##
## LEF for PtnCells ;
## created by Innovus v15.23-s045_1 on Sat Mar 21 00:23:04 2026
##

VERSION 5.8 ;

BUSBITCHARS "[]" ;
DIVIDERCHAR "/" ;

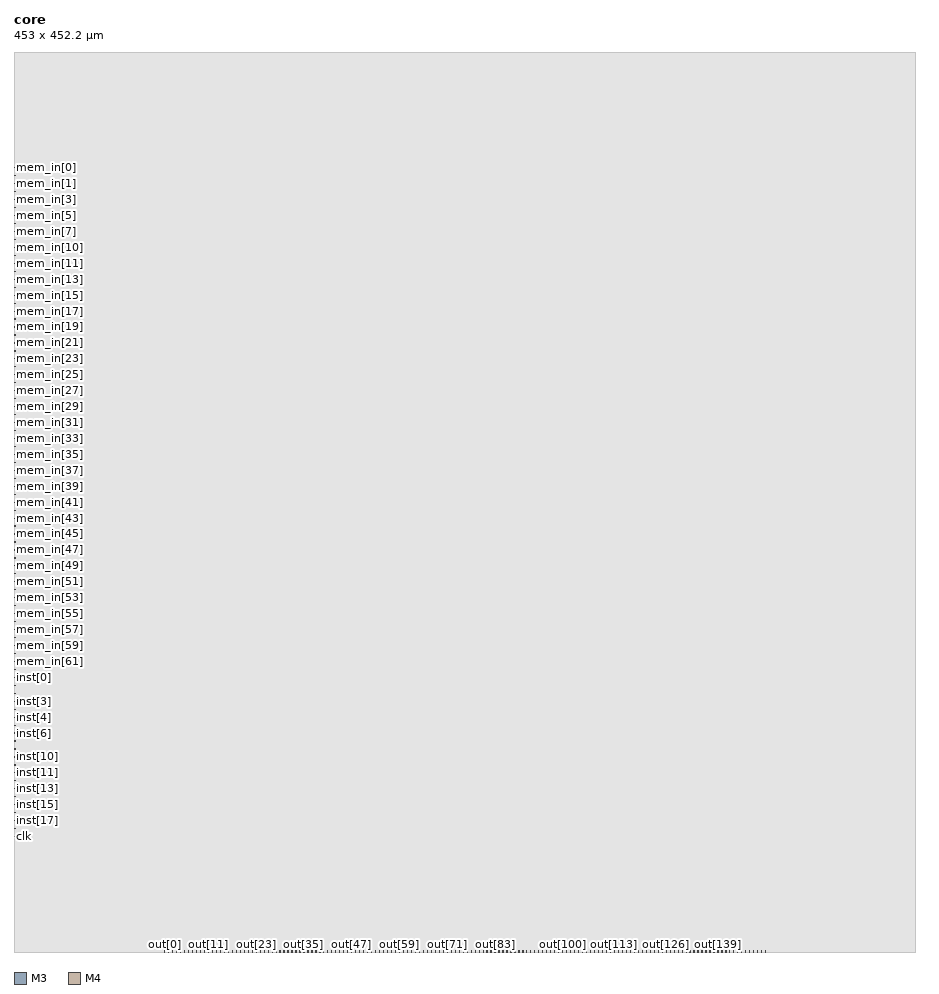
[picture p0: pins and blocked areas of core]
MACRO core
  CLASS BLOCK ;
  SIZE 453.0000 BY 452.2000 ;
  FOREIGN core 0.0000 0.0000 ;
  ORIGIN 0 0 ;
  SYMMETRY X Y R90 ;
  PIN clk
    DIRECTION INPUT ;
    USE SIGNAL ;
    PORT
      LAYER M3 ;
        RECT 0.0000 57.9500 0.5200 58.0500 ;
    END
  END clk
  PIN mem_in[63]
    DIRECTION INPUT ;
    USE SIGNAL ;
    PORT
      LAYER M3 ;
        RECT 0.0000 141.9500 0.5200 142.0500 ;
    END
  END mem_in[63]
  PIN mem_in[62]
    DIRECTION INPUT ;
    USE SIGNAL ;
    PORT
      LAYER M3 ;
        RECT 0.0000 145.9500 0.5200 146.0500 ;
    END
  END mem_in[62]
  PIN mem_in[61]
    DIRECTION INPUT ;
    USE SIGNAL ;
    PORT
      LAYER M3 ;
        RECT 0.0000 149.9500 0.5200 150.0500 ;
    END
  END mem_in[61]
  PIN mem_in[60]
    DIRECTION INPUT ;
    USE SIGNAL ;
    PORT
      LAYER M3 ;
        RECT 0.0000 153.9500 0.5200 154.0500 ;
    END
  END mem_in[60]
  PIN mem_in[59]
    DIRECTION INPUT ;
    USE SIGNAL ;
    PORT
      LAYER M3 ;
        RECT 0.0000 157.9500 0.5200 158.0500 ;
    END
  END mem_in[59]
  PIN mem_in[58]
    DIRECTION INPUT ;
    USE SIGNAL ;
    PORT
      LAYER M3 ;
        RECT 0.0000 161.9500 0.5200 162.0500 ;
    END
  END mem_in[58]
  PIN mem_in[57]
    DIRECTION INPUT ;
    USE SIGNAL ;
    PORT
      LAYER M3 ;
        RECT 0.0000 165.9500 0.5200 166.0500 ;
    END
  END mem_in[57]
  PIN mem_in[56]
    DIRECTION INPUT ;
    USE SIGNAL ;
    PORT
      LAYER M3 ;
        RECT 0.0000 169.9500 0.5200 170.0500 ;
    END
  END mem_in[56]
  PIN mem_in[55]
    DIRECTION INPUT ;
    USE SIGNAL ;
    PORT
      LAYER M3 ;
        RECT 0.0000 173.9500 0.5200 174.0500 ;
    END
  END mem_in[55]
  PIN mem_in[54]
    DIRECTION INPUT ;
    USE SIGNAL ;
    PORT
      LAYER M3 ;
        RECT 0.0000 177.9500 0.5200 178.0500 ;
    END
  END mem_in[54]
  PIN mem_in[53]
    DIRECTION INPUT ;
    USE SIGNAL ;
    PORT
      LAYER M3 ;
        RECT 0.0000 181.9500 0.5200 182.0500 ;
    END
  END mem_in[53]
  PIN mem_in[52]
    DIRECTION INPUT ;
    USE SIGNAL ;
    PORT
      LAYER M3 ;
        RECT 0.0000 185.9500 0.5200 186.0500 ;
    END
  END mem_in[52]
  PIN mem_in[51]
    DIRECTION INPUT ;
    USE SIGNAL ;
    PORT
      LAYER M3 ;
        RECT 0.0000 189.9500 0.5200 190.0500 ;
    END
  END mem_in[51]
  PIN mem_in[50]
    DIRECTION INPUT ;
    USE SIGNAL ;
    PORT
      LAYER M3 ;
        RECT 0.0000 193.9500 0.5200 194.0500 ;
    END
  END mem_in[50]
  PIN mem_in[49]
    DIRECTION INPUT ;
    USE SIGNAL ;
    PORT
      LAYER M3 ;
        RECT 0.0000 197.9500 0.5200 198.0500 ;
    END
  END mem_in[49]
  PIN mem_in[48]
    DIRECTION INPUT ;
    USE SIGNAL ;
    PORT
      LAYER M3 ;
        RECT 0.0000 201.9500 0.5200 202.0500 ;
    END
  END mem_in[48]
  PIN mem_in[47]
    DIRECTION INPUT ;
    USE SIGNAL ;
    PORT
      LAYER M3 ;
        RECT 0.0000 205.9500 0.5200 206.0500 ;
    END
  END mem_in[47]
  PIN mem_in[46]
    DIRECTION INPUT ;
    USE SIGNAL ;
    PORT
      LAYER M3 ;
        RECT 0.0000 209.9500 0.5200 210.0500 ;
    END
  END mem_in[46]
  PIN mem_in[45]
    DIRECTION INPUT ;
    USE SIGNAL ;
    PORT
      LAYER M3 ;
        RECT 0.0000 213.9500 0.5200 214.0500 ;
    END
  END mem_in[45]
  PIN mem_in[44]
    DIRECTION INPUT ;
    USE SIGNAL ;
    PORT
      LAYER M3 ;
        RECT 0.0000 217.9500 0.5200 218.0500 ;
    END
  END mem_in[44]
  PIN mem_in[43]
    DIRECTION INPUT ;
    USE SIGNAL ;
    PORT
      LAYER M3 ;
        RECT 0.0000 221.9500 0.5200 222.0500 ;
    END
  END mem_in[43]
  PIN mem_in[42]
    DIRECTION INPUT ;
    USE SIGNAL ;
    PORT
      LAYER M3 ;
        RECT 0.0000 225.9500 0.5200 226.0500 ;
    END
  END mem_in[42]
  PIN mem_in[41]
    DIRECTION INPUT ;
    USE SIGNAL ;
    PORT
      LAYER M3 ;
        RECT 0.0000 229.9500 0.5200 230.0500 ;
    END
  END mem_in[41]
  PIN mem_in[40]
    DIRECTION INPUT ;
    USE SIGNAL ;
    PORT
      LAYER M3 ;
        RECT 0.0000 233.9500 0.5200 234.0500 ;
    END
  END mem_in[40]
  PIN mem_in[39]
    DIRECTION INPUT ;
    USE SIGNAL ;
    PORT
      LAYER M3 ;
        RECT 0.0000 237.9500 0.5200 238.0500 ;
    END
  END mem_in[39]
  PIN mem_in[38]
    DIRECTION INPUT ;
    USE SIGNAL ;
    PORT
      LAYER M3 ;
        RECT 0.0000 241.9500 0.5200 242.0500 ;
    END
  END mem_in[38]
  PIN mem_in[37]
    DIRECTION INPUT ;
    USE SIGNAL ;
    PORT
      LAYER M3 ;
        RECT 0.0000 245.9500 0.5200 246.0500 ;
    END
  END mem_in[37]
  PIN mem_in[36]
    DIRECTION INPUT ;
    USE SIGNAL ;
    PORT
      LAYER M3 ;
        RECT 0.0000 249.9500 0.5200 250.0500 ;
    END
  END mem_in[36]
  PIN mem_in[35]
    DIRECTION INPUT ;
    USE SIGNAL ;
    PORT
      LAYER M3 ;
        RECT 0.0000 253.9500 0.5200 254.0500 ;
    END
  END mem_in[35]
  PIN mem_in[34]
    DIRECTION INPUT ;
    USE SIGNAL ;
    PORT
      LAYER M3 ;
        RECT 0.0000 257.9500 0.5200 258.0500 ;
    END
  END mem_in[34]
  PIN mem_in[33]
    DIRECTION INPUT ;
    USE SIGNAL ;
    PORT
      LAYER M3 ;
        RECT 0.0000 261.9500 0.5200 262.0500 ;
    END
  END mem_in[33]
  PIN mem_in[32]
    DIRECTION INPUT ;
    USE SIGNAL ;
    PORT
      LAYER M3 ;
        RECT 0.0000 265.9500 0.5200 266.0500 ;
    END
  END mem_in[32]
  PIN mem_in[31]
    DIRECTION INPUT ;
    USE SIGNAL ;
    PORT
      LAYER M3 ;
        RECT 0.0000 269.9500 0.5200 270.0500 ;
    END
  END mem_in[31]
  PIN mem_in[30]
    DIRECTION INPUT ;
    USE SIGNAL ;
    PORT
      LAYER M3 ;
        RECT 0.0000 273.9500 0.5200 274.0500 ;
    END
  END mem_in[30]
  PIN mem_in[29]
    DIRECTION INPUT ;
    USE SIGNAL ;
    PORT
      LAYER M3 ;
        RECT 0.0000 277.9500 0.5200 278.0500 ;
    END
  END mem_in[29]
  PIN mem_in[28]
    DIRECTION INPUT ;
    USE SIGNAL ;
    PORT
      LAYER M3 ;
        RECT 0.0000 281.9500 0.5200 282.0500 ;
    END
  END mem_in[28]
  PIN mem_in[27]
    DIRECTION INPUT ;
    USE SIGNAL ;
    PORT
      LAYER M3 ;
        RECT 0.0000 285.9500 0.5200 286.0500 ;
    END
  END mem_in[27]
  PIN mem_in[26]
    DIRECTION INPUT ;
    USE SIGNAL ;
    PORT
      LAYER M3 ;
        RECT 0.0000 289.9500 0.5200 290.0500 ;
    END
  END mem_in[26]
  PIN mem_in[25]
    DIRECTION INPUT ;
    USE SIGNAL ;
    PORT
      LAYER M3 ;
        RECT 0.0000 293.9500 0.5200 294.0500 ;
    END
  END mem_in[25]
  PIN mem_in[24]
    DIRECTION INPUT ;
    USE SIGNAL ;
    PORT
      LAYER M3 ;
        RECT 0.0000 297.9500 0.5200 298.0500 ;
    END
  END mem_in[24]
  PIN mem_in[23]
    DIRECTION INPUT ;
    USE SIGNAL ;
    PORT
      LAYER M3 ;
        RECT 0.0000 301.9500 0.5200 302.0500 ;
    END
  END mem_in[23]
  PIN mem_in[22]
    DIRECTION INPUT ;
    USE SIGNAL ;
    PORT
      LAYER M3 ;
        RECT 0.0000 305.9500 0.5200 306.0500 ;
    END
  END mem_in[22]
  PIN mem_in[21]
    DIRECTION INPUT ;
    USE SIGNAL ;
    PORT
      LAYER M3 ;
        RECT 0.0000 309.9500 0.5200 310.0500 ;
    END
  END mem_in[21]
  PIN mem_in[20]
    DIRECTION INPUT ;
    USE SIGNAL ;
    PORT
      LAYER M3 ;
        RECT 0.0000 313.9500 0.5200 314.0500 ;
    END
  END mem_in[20]
  PIN mem_in[19]
    DIRECTION INPUT ;
    USE SIGNAL ;
    PORT
      LAYER M3 ;
        RECT 0.0000 317.9500 0.5200 318.0500 ;
    END
  END mem_in[19]
  PIN mem_in[18]
    DIRECTION INPUT ;
    USE SIGNAL ;
    PORT
      LAYER M3 ;
        RECT 0.0000 321.9500 0.5200 322.0500 ;
    END
  END mem_in[18]
  PIN mem_in[17]
    DIRECTION INPUT ;
    USE SIGNAL ;
    PORT
      LAYER M3 ;
        RECT 0.0000 325.9500 0.5200 326.0500 ;
    END
  END mem_in[17]
  PIN mem_in[16]
    DIRECTION INPUT ;
    USE SIGNAL ;
    PORT
      LAYER M3 ;
        RECT 0.0000 329.9500 0.5200 330.0500 ;
    END
  END mem_in[16]
  PIN mem_in[15]
    DIRECTION INPUT ;
    USE SIGNAL ;
    PORT
      LAYER M3 ;
        RECT 0.0000 333.9500 0.5200 334.0500 ;
    END
  END mem_in[15]
  PIN mem_in[14]
    DIRECTION INPUT ;
    USE SIGNAL ;
    PORT
      LAYER M3 ;
        RECT 0.0000 337.9500 0.5200 338.0500 ;
    END
  END mem_in[14]
  PIN mem_in[13]
    DIRECTION INPUT ;
    USE SIGNAL ;
    PORT
      LAYER M3 ;
        RECT 0.0000 341.9500 0.5200 342.0500 ;
    END
  END mem_in[13]
  PIN mem_in[12]
    DIRECTION INPUT ;
    USE SIGNAL ;
    PORT
      LAYER M3 ;
        RECT 0.0000 345.9500 0.5200 346.0500 ;
    END
  END mem_in[12]
  PIN mem_in[11]
    DIRECTION INPUT ;
    USE SIGNAL ;
    PORT
      LAYER M3 ;
        RECT 0.0000 349.9500 0.5200 350.0500 ;
    END
  END mem_in[11]
  PIN mem_in[10]
    DIRECTION INPUT ;
    USE SIGNAL ;
    PORT
      LAYER M3 ;
        RECT 0.0000 353.9500 0.5200 354.0500 ;
    END
  END mem_in[10]
  PIN mem_in[9]
    DIRECTION INPUT ;
    USE SIGNAL ;
    PORT
      LAYER M3 ;
        RECT 0.0000 357.9500 0.5200 358.0500 ;
    END
  END mem_in[9]
  PIN mem_in[8]
    DIRECTION INPUT ;
    USE SIGNAL ;
    PORT
      LAYER M3 ;
        RECT 0.0000 361.9500 0.5200 362.0500 ;
    END
  END mem_in[8]
  PIN mem_in[7]
    DIRECTION INPUT ;
    USE SIGNAL ;
    PORT
      LAYER M3 ;
        RECT 0.0000 365.9500 0.5200 366.0500 ;
    END
  END mem_in[7]
  PIN mem_in[6]
    DIRECTION INPUT ;
    USE SIGNAL ;
    PORT
      LAYER M3 ;
        RECT 0.0000 369.9500 0.5200 370.0500 ;
    END
  END mem_in[6]
  PIN mem_in[5]
    DIRECTION INPUT ;
    USE SIGNAL ;
    PORT
      LAYER M3 ;
        RECT 0.0000 373.9500 0.5200 374.0500 ;
    END
  END mem_in[5]
  PIN mem_in[4]
    DIRECTION INPUT ;
    USE SIGNAL ;
    PORT
      LAYER M3 ;
        RECT 0.0000 377.9500 0.5200 378.0500 ;
    END
  END mem_in[4]
  PIN mem_in[3]
    DIRECTION INPUT ;
    USE SIGNAL ;
    PORT
      LAYER M3 ;
        RECT 0.0000 381.9500 0.5200 382.0500 ;
    END
  END mem_in[3]
  PIN mem_in[2]
    DIRECTION INPUT ;
    USE SIGNAL ;
    PORT
      LAYER M3 ;
        RECT 0.0000 385.9500 0.5200 386.0500 ;
    END
  END mem_in[2]
  PIN mem_in[1]
    DIRECTION INPUT ;
    USE SIGNAL ;
    PORT
      LAYER M3 ;
        RECT 0.0000 389.9500 0.5200 390.0500 ;
    END
  END mem_in[1]
  PIN mem_in[0]
    DIRECTION INPUT ;
    USE SIGNAL ;
    PORT
      LAYER M3 ;
        RECT 0.0000 393.9500 0.5200 394.0500 ;
    END
  END mem_in[0]
  PIN inst[18]
    DIRECTION INPUT ;
    USE SIGNAL ;
    PORT
      LAYER M3 ;
        RECT 0.0000 65.9500 0.5200 66.0500 ;
    END
  END inst[18]
  PIN inst[17]
    DIRECTION INPUT ;
    USE SIGNAL ;
    PORT
      LAYER M3 ;
        RECT 0.0000 69.9500 0.5200 70.0500 ;
    END
  END inst[17]
  PIN inst[16]
    DIRECTION INPUT ;
    USE SIGNAL ;
    PORT
      LAYER M3 ;
        RECT 0.0000 73.9500 0.5200 74.0500 ;
    END
  END inst[16]
  PIN inst[15]
    DIRECTION INPUT ;
    USE SIGNAL ;
    PORT
      LAYER M3 ;
        RECT 0.0000 77.9500 0.5200 78.0500 ;
    END
  END inst[15]
  PIN inst[14]
    DIRECTION INPUT ;
    USE SIGNAL ;
    PORT
      LAYER M3 ;
        RECT 0.0000 81.9500 0.5200 82.0500 ;
    END
  END inst[14]
  PIN inst[13]
    DIRECTION INPUT ;
    USE SIGNAL ;
    PORT
      LAYER M3 ;
        RECT 0.0000 85.9500 0.5200 86.0500 ;
    END
  END inst[13]
  PIN inst[12]
    DIRECTION INPUT ;
    USE SIGNAL ;
    PORT
      LAYER M3 ;
        RECT 0.0000 89.9500 0.5200 90.0500 ;
    END
  END inst[12]
  PIN inst[11]
    DIRECTION INPUT ;
    USE SIGNAL ;
    PORT
      LAYER M3 ;
        RECT 0.0000 93.9500 0.5200 94.0500 ;
    END
  END inst[11]
  PIN inst[10]
    DIRECTION INPUT ;
    USE SIGNAL ;
    PORT
      LAYER M3 ;
        RECT 0.0000 97.9500 0.5200 98.0500 ;
    END
  END inst[10]
  PIN inst[9]
    DIRECTION INPUT ;
    USE SIGNAL ;
    PORT
      LAYER M3 ;
        RECT 0.0000 101.9500 0.5200 102.0500 ;
    END
  END inst[9]
  PIN inst[8]
    DIRECTION INPUT ;
    USE SIGNAL ;
    PORT
      LAYER M3 ;
        RECT 0.0000 105.9500 0.5200 106.0500 ;
    END
  END inst[8]
  PIN inst[7]
    DIRECTION INPUT ;
    USE SIGNAL ;
    PORT
      LAYER M3 ;
        RECT 0.0000 109.9500 0.5200 110.0500 ;
    END
  END inst[7]
  PIN inst[6]
    DIRECTION INPUT ;
    USE SIGNAL ;
    PORT
      LAYER M3 ;
        RECT 0.0000 113.9500 0.5200 114.0500 ;
    END
  END inst[6]
  PIN inst[5]
    DIRECTION INPUT ;
    USE SIGNAL ;
    PORT
      LAYER M3 ;
        RECT 0.0000 117.9500 0.5200 118.0500 ;
    END
  END inst[5]
  PIN inst[4]
    DIRECTION INPUT ;
    USE SIGNAL ;
    PORT
      LAYER M3 ;
        RECT 0.0000 121.9500 0.5200 122.0500 ;
    END
  END inst[4]
  PIN inst[3]
    DIRECTION INPUT ;
    USE SIGNAL ;
    PORT
      LAYER M3 ;
        RECT 0.0000 125.9500 0.5200 126.0500 ;
    END
  END inst[3]
  PIN inst[2]
    DIRECTION INPUT ;
    USE SIGNAL ;
    PORT
      LAYER M3 ;
        RECT 0.0000 129.9500 0.5200 130.0500 ;
    END
  END inst[2]
  PIN inst[1]
    DIRECTION INPUT ;
    USE SIGNAL ;
    PORT
      LAYER M3 ;
        RECT 0.0000 133.9500 0.5200 134.0500 ;
    END
  END inst[1]
  PIN inst[0]
    DIRECTION INPUT ;
    USE SIGNAL ;
    PORT
      LAYER M3 ;
        RECT 0.0000 137.9500 0.5200 138.0500 ;
    END
  END inst[0]
  PIN reset
    DIRECTION INPUT ;
    USE SIGNAL ;
    PORT
      LAYER M3 ;
        RECT 0.0000 61.9500 0.5200 62.0500 ;
    END
  END reset
  PIN out[151]
    DIRECTION OUTPUT ;
    USE SIGNAL ;
    PORT
      LAYER M4 ;
        RECT 377.6500 0.0000 377.7500 0.5200 ;
    END
  END out[151]
  PIN out[150]
    DIRECTION OUTPUT ;
    USE SIGNAL ;
    PORT
      LAYER M4 ;
        RECT 375.6500 0.0000 375.7500 0.5200 ;
    END
  END out[150]
  PIN out[149]
    DIRECTION OUTPUT ;
    USE SIGNAL ;
    PORT
      LAYER M4 ;
        RECT 373.6500 0.0000 373.7500 0.5200 ;
    END
  END out[149]
  PIN out[148]
    DIRECTION OUTPUT ;
    USE SIGNAL ;
    PORT
      LAYER M4 ;
        RECT 371.6500 0.0000 371.7500 0.5200 ;
    END
  END out[148]
  PIN out[147]
    DIRECTION OUTPUT ;
    USE SIGNAL ;
    PORT
      LAYER M4 ;
        RECT 369.6500 0.0000 369.7500 0.5200 ;
    END
  END out[147]
  PIN out[146]
    DIRECTION OUTPUT ;
    USE SIGNAL ;
    PORT
      LAYER M4 ;
        RECT 367.6500 0.0000 367.7500 0.5200 ;
    END
  END out[146]
  PIN out[145]
    DIRECTION OUTPUT ;
    USE SIGNAL ;
    PORT
      LAYER M4 ;
        RECT 365.6500 0.0000 365.7500 0.5200 ;
    END
  END out[145]
  PIN out[144]
    DIRECTION OUTPUT ;
    USE SIGNAL ;
    PORT
      LAYER M4 ;
        RECT 363.6500 0.0000 363.7500 0.5200 ;
    END
  END out[144]
  PIN out[143]
    DIRECTION OUTPUT ;
    USE SIGNAL ;
    PORT
      LAYER M4 ;
        RECT 361.6500 0.0000 361.7500 0.5200 ;
    END
  END out[143]
  PIN out[142]
    DIRECTION OUTPUT ;
    USE SIGNAL ;
    PORT
      LAYER M4 ;
        RECT 359.6500 0.0000 359.7500 0.5200 ;
    END
  END out[142]
  PIN out[141]
    DIRECTION OUTPUT ;
    USE SIGNAL ;
    PORT
      LAYER M4 ;
        RECT 357.6500 0.0000 357.7500 0.5200 ;
    END
  END out[141]
  PIN out[140]
    DIRECTION OUTPUT ;
    USE SIGNAL ;
    PORT
      LAYER M4 ;
        RECT 355.6500 0.0000 355.7500 0.5200 ;
    END
  END out[140]
  PIN out[139]
    DIRECTION OUTPUT ;
    USE SIGNAL ;
    PORT
      LAYER M4 ;
        RECT 353.6500 0.0000 353.7500 0.5200 ;
    END
  END out[139]
  PIN out[138]
    DIRECTION OUTPUT ;
    USE SIGNAL ;
    PORT
      LAYER M4 ;
        RECT 351.6500 0.0000 351.7500 0.5200 ;
    END
  END out[138]
  PIN out[137]
    DIRECTION OUTPUT ;
    USE SIGNAL ;
    PORT
      LAYER M4 ;
        RECT 349.6500 0.0000 349.7500 0.5200 ;
    END
  END out[137]
  PIN out[136]
    DIRECTION OUTPUT ;
    USE SIGNAL ;
    PORT
      LAYER M4 ;
        RECT 347.6500 0.0000 347.7500 0.5200 ;
    END
  END out[136]
  PIN out[135]
    DIRECTION OUTPUT ;
    USE SIGNAL ;
    PORT
      LAYER M4 ;
        RECT 345.6500 0.0000 345.7500 0.5200 ;
    END
  END out[135]
  PIN out[134]
    DIRECTION OUTPUT ;
    USE SIGNAL ;
    PORT
      LAYER M4 ;
        RECT 343.6500 0.0000 343.7500 0.5200 ;
    END
  END out[134]
  PIN out[133]
    DIRECTION OUTPUT ;
    USE SIGNAL ;
    PORT
      LAYER M4 ;
        RECT 341.6500 0.0000 341.7500 0.5200 ;
    END
  END out[133]
  PIN out[132]
    DIRECTION OUTPUT ;
    USE SIGNAL ;
    PORT
      LAYER M4 ;
        RECT 339.6500 0.0000 339.7500 0.5200 ;
    END
  END out[132]
  PIN out[131]
    DIRECTION OUTPUT ;
    USE SIGNAL ;
    PORT
      LAYER M4 ;
        RECT 337.6500 0.0000 337.7500 0.5200 ;
    END
  END out[131]
  PIN out[130]
    DIRECTION OUTPUT ;
    USE SIGNAL ;
    PORT
      LAYER M4 ;
        RECT 335.6500 0.0000 335.7500 0.5200 ;
    END
  END out[130]
  PIN out[129]
    DIRECTION OUTPUT ;
    USE SIGNAL ;
    PORT
      LAYER M4 ;
        RECT 333.6500 0.0000 333.7500 0.5200 ;
    END
  END out[129]
  PIN out[128]
    DIRECTION OUTPUT ;
    USE SIGNAL ;
    PORT
      LAYER M4 ;
        RECT 331.6500 0.0000 331.7500 0.5200 ;
    END
  END out[128]
  PIN out[127]
    DIRECTION OUTPUT ;
    USE SIGNAL ;
    PORT
      LAYER M4 ;
        RECT 329.6500 0.0000 329.7500 0.5200 ;
    END
  END out[127]
  PIN out[126]
    DIRECTION OUTPUT ;
    USE SIGNAL ;
    PORT
      LAYER M4 ;
        RECT 327.6500 0.0000 327.7500 0.5200 ;
    END
  END out[126]
  PIN out[125]
    DIRECTION OUTPUT ;
    USE SIGNAL ;
    PORT
      LAYER M4 ;
        RECT 325.6500 0.0000 325.7500 0.5200 ;
    END
  END out[125]
  PIN out[124]
    DIRECTION OUTPUT ;
    USE SIGNAL ;
    PORT
      LAYER M4 ;
        RECT 323.6500 0.0000 323.7500 0.5200 ;
    END
  END out[124]
  PIN out[123]
    DIRECTION OUTPUT ;
    USE SIGNAL ;
    PORT
      LAYER M4 ;
        RECT 321.6500 0.0000 321.7500 0.5200 ;
    END
  END out[123]
  PIN out[122]
    DIRECTION OUTPUT ;
    USE SIGNAL ;
    PORT
      LAYER M4 ;
        RECT 319.6500 0.0000 319.7500 0.5200 ;
    END
  END out[122]
  PIN out[121]
    DIRECTION OUTPUT ;
    USE SIGNAL ;
    PORT
      LAYER M4 ;
        RECT 317.6500 0.0000 317.7500 0.5200 ;
    END
  END out[121]
  PIN out[120]
    DIRECTION OUTPUT ;
    USE SIGNAL ;
    PORT
      LAYER M4 ;
        RECT 315.6500 0.0000 315.7500 0.5200 ;
    END
  END out[120]
  PIN out[119]
    DIRECTION OUTPUT ;
    USE SIGNAL ;
    PORT
      LAYER M4 ;
        RECT 313.6500 0.0000 313.7500 0.5200 ;
    END
  END out[119]
  PIN out[118]
    DIRECTION OUTPUT ;
    USE SIGNAL ;
    PORT
      LAYER M4 ;
        RECT 311.6500 0.0000 311.7500 0.5200 ;
    END
  END out[118]
  PIN out[117]
    DIRECTION OUTPUT ;
    USE SIGNAL ;
    PORT
      LAYER M4 ;
        RECT 309.6500 0.0000 309.7500 0.5200 ;
    END
  END out[117]
  PIN out[116]
    DIRECTION OUTPUT ;
    USE SIGNAL ;
    PORT
      LAYER M4 ;
        RECT 307.6500 0.0000 307.7500 0.5200 ;
    END
  END out[116]
  PIN out[115]
    DIRECTION OUTPUT ;
    USE SIGNAL ;
    PORT
      LAYER M4 ;
        RECT 305.6500 0.0000 305.7500 0.5200 ;
    END
  END out[115]
  PIN out[114]
    DIRECTION OUTPUT ;
    USE SIGNAL ;
    PORT
      LAYER M4 ;
        RECT 303.6500 0.0000 303.7500 0.5200 ;
    END
  END out[114]
  PIN out[113]
    DIRECTION OUTPUT ;
    USE SIGNAL ;
    PORT
      LAYER M4 ;
        RECT 301.6500 0.0000 301.7500 0.5200 ;
    END
  END out[113]
  PIN out[112]
    DIRECTION OUTPUT ;
    USE SIGNAL ;
    PORT
      LAYER M4 ;
        RECT 299.6500 0.0000 299.7500 0.5200 ;
    END
  END out[112]
  PIN out[111]
    DIRECTION OUTPUT ;
    USE SIGNAL ;
    PORT
      LAYER M4 ;
        RECT 297.6500 0.0000 297.7500 0.5200 ;
    END
  END out[111]
  PIN out[110]
    DIRECTION OUTPUT ;
    USE SIGNAL ;
    PORT
      LAYER M4 ;
        RECT 295.6500 0.0000 295.7500 0.5200 ;
    END
  END out[110]
  PIN out[109]
    DIRECTION OUTPUT ;
    USE SIGNAL ;
    PORT
      LAYER M4 ;
        RECT 293.6500 0.0000 293.7500 0.5200 ;
    END
  END out[109]
  PIN out[108]
    DIRECTION OUTPUT ;
    USE SIGNAL ;
    PORT
      LAYER M4 ;
        RECT 291.6500 0.0000 291.7500 0.5200 ;
    END
  END out[108]
  PIN out[107]
    DIRECTION OUTPUT ;
    USE SIGNAL ;
    PORT
      LAYER M4 ;
        RECT 289.6500 0.0000 289.7500 0.5200 ;
    END
  END out[107]
  PIN out[106]
    DIRECTION OUTPUT ;
    USE SIGNAL ;
    PORT
      LAYER M4 ;
        RECT 287.6500 0.0000 287.7500 0.5200 ;
    END
  END out[106]
  PIN out[105]
    DIRECTION OUTPUT ;
    USE SIGNAL ;
    PORT
      LAYER M4 ;
        RECT 285.6500 0.0000 285.7500 0.5200 ;
    END
  END out[105]
  PIN out[104]
    DIRECTION OUTPUT ;
    USE SIGNAL ;
    PORT
      LAYER M4 ;
        RECT 283.6500 0.0000 283.7500 0.5200 ;
    END
  END out[104]
  PIN out[103]
    DIRECTION OUTPUT ;
    USE SIGNAL ;
    PORT
      LAYER M4 ;
        RECT 281.6500 0.0000 281.7500 0.5200 ;
    END
  END out[103]
  PIN out[102]
    DIRECTION OUTPUT ;
    USE SIGNAL ;
    PORT
      LAYER M4 ;
        RECT 279.6500 0.0000 279.7500 0.5200 ;
    END
  END out[102]
  PIN out[101]
    DIRECTION OUTPUT ;
    USE SIGNAL ;
    PORT
      LAYER M4 ;
        RECT 277.6500 0.0000 277.7500 0.5200 ;
    END
  END out[101]
  PIN out[100]
    DIRECTION OUTPUT ;
    USE SIGNAL ;
    PORT
      LAYER M4 ;
        RECT 275.6500 0.0000 275.7500 0.5200 ;
    END
  END out[100]
  PIN out[99]
    DIRECTION OUTPUT ;
    USE SIGNAL ;
    PORT
      LAYER M4 ;
        RECT 273.6500 0.0000 273.7500 0.5200 ;
    END
  END out[99]
  PIN out[98]
    DIRECTION OUTPUT ;
    USE SIGNAL ;
    PORT
      LAYER M4 ;
        RECT 271.6500 0.0000 271.7500 0.5200 ;
    END
  END out[98]
  PIN out[97]
    DIRECTION OUTPUT ;
    USE SIGNAL ;
    PORT
      LAYER M4 ;
        RECT 269.6500 0.0000 269.7500 0.5200 ;
    END
  END out[97]
  PIN out[96]
    DIRECTION OUTPUT ;
    USE SIGNAL ;
    PORT
      LAYER M4 ;
        RECT 267.6500 0.0000 267.7500 0.5200 ;
    END
  END out[96]
  PIN out[95]
    DIRECTION OUTPUT ;
    USE SIGNAL ;
    PORT
      LAYER M4 ;
        RECT 265.6500 0.0000 265.7500 0.5200 ;
    END
  END out[95]
  PIN out[94]
    DIRECTION OUTPUT ;
    USE SIGNAL ;
    PORT
      LAYER M4 ;
        RECT 263.6500 0.0000 263.7500 0.5200 ;
    END
  END out[94]
  PIN out[93]
    DIRECTION OUTPUT ;
    USE SIGNAL ;
    PORT
      LAYER M4 ;
        RECT 261.6500 0.0000 261.7500 0.5200 ;
    END
  END out[93]
  PIN out[92]
    DIRECTION OUTPUT ;
    USE SIGNAL ;
    PORT
      LAYER M4 ;
        RECT 259.6500 0.0000 259.7500 0.5200 ;
    END
  END out[92]
  PIN out[91]
    DIRECTION OUTPUT ;
    USE SIGNAL ;
    PORT
      LAYER M4 ;
        RECT 257.6500 0.0000 257.7500 0.5200 ;
    END
  END out[91]
  PIN out[90]
    DIRECTION OUTPUT ;
    USE SIGNAL ;
    PORT
      LAYER M4 ;
        RECT 255.6500 0.0000 255.7500 0.5200 ;
    END
  END out[90]
  PIN out[89]
    DIRECTION OUTPUT ;
    USE SIGNAL ;
    PORT
      LAYER M4 ;
        RECT 253.6500 0.0000 253.7500 0.5200 ;
    END
  END out[89]
  PIN out[88]
    DIRECTION OUTPUT ;
    USE SIGNAL ;
    PORT
      LAYER M4 ;
        RECT 251.6500 0.0000 251.7500 0.5200 ;
    END
  END out[88]
  PIN out[87]
    DIRECTION OUTPUT ;
    USE SIGNAL ;
    PORT
      LAYER M4 ;
        RECT 249.6500 0.0000 249.7500 0.5200 ;
    END
  END out[87]
  PIN out[86]
    DIRECTION OUTPUT ;
    USE SIGNAL ;
    PORT
      LAYER M4 ;
        RECT 247.6500 0.0000 247.7500 0.5200 ;
    END
  END out[86]
  PIN out[85]
    DIRECTION OUTPUT ;
    USE SIGNAL ;
    PORT
      LAYER M4 ;
        RECT 245.6500 0.0000 245.7500 0.5200 ;
    END
  END out[85]
  PIN out[84]
    DIRECTION OUTPUT ;
    USE SIGNAL ;
    PORT
      LAYER M4 ;
        RECT 243.6500 0.0000 243.7500 0.5200 ;
    END
  END out[84]
  PIN out[83]
    DIRECTION OUTPUT ;
    USE SIGNAL ;
    PORT
      LAYER M4 ;
        RECT 241.6500 0.0000 241.7500 0.5200 ;
    END
  END out[83]
  PIN out[82]
    DIRECTION OUTPUT ;
    USE SIGNAL ;
    PORT
      LAYER M4 ;
        RECT 239.6500 0.0000 239.7500 0.5200 ;
    END
  END out[82]
  PIN out[81]
    DIRECTION OUTPUT ;
    USE SIGNAL ;
    PORT
      LAYER M4 ;
        RECT 237.6500 0.0000 237.7500 0.5200 ;
    END
  END out[81]
  PIN out[80]
    DIRECTION OUTPUT ;
    USE SIGNAL ;
    PORT
      LAYER M4 ;
        RECT 235.6500 0.0000 235.7500 0.5200 ;
    END
  END out[80]
  PIN out[79]
    DIRECTION OUTPUT ;
    USE SIGNAL ;
    PORT
      LAYER M4 ;
        RECT 233.6500 0.0000 233.7500 0.5200 ;
    END
  END out[79]
  PIN out[78]
    DIRECTION OUTPUT ;
    USE SIGNAL ;
    PORT
      LAYER M4 ;
        RECT 231.6500 0.0000 231.7500 0.5200 ;
    END
  END out[78]
  PIN out[77]
    DIRECTION OUTPUT ;
    USE SIGNAL ;
    PORT
      LAYER M4 ;
        RECT 229.6500 0.0000 229.7500 0.5200 ;
    END
  END out[77]
  PIN out[76]
    DIRECTION OUTPUT ;
    USE SIGNAL ;
    PORT
      LAYER M4 ;
        RECT 227.6500 0.0000 227.7500 0.5200 ;
    END
  END out[76]
  PIN out[75]
    DIRECTION OUTPUT ;
    USE SIGNAL ;
    PORT
      LAYER M4 ;
        RECT 225.6500 0.0000 225.7500 0.5200 ;
    END
  END out[75]
  PIN out[74]
    DIRECTION OUTPUT ;
    USE SIGNAL ;
    PORT
      LAYER M4 ;
        RECT 223.6500 0.0000 223.7500 0.5200 ;
    END
  END out[74]
  PIN out[73]
    DIRECTION OUTPUT ;
    USE SIGNAL ;
    PORT
      LAYER M4 ;
        RECT 221.6500 0.0000 221.7500 0.5200 ;
    END
  END out[73]
  PIN out[72]
    DIRECTION OUTPUT ;
    USE SIGNAL ;
    PORT
      LAYER M4 ;
        RECT 219.6500 0.0000 219.7500 0.5200 ;
    END
  END out[72]
  PIN out[71]
    DIRECTION OUTPUT ;
    USE SIGNAL ;
    PORT
      LAYER M4 ;
        RECT 217.6500 0.0000 217.7500 0.5200 ;
    END
  END out[71]
  PIN out[70]
    DIRECTION OUTPUT ;
    USE SIGNAL ;
    PORT
      LAYER M4 ;
        RECT 215.6500 0.0000 215.7500 0.5200 ;
    END
  END out[70]
  PIN out[69]
    DIRECTION OUTPUT ;
    USE SIGNAL ;
    PORT
      LAYER M4 ;
        RECT 213.6500 0.0000 213.7500 0.5200 ;
    END
  END out[69]
  PIN out[68]
    DIRECTION OUTPUT ;
    USE SIGNAL ;
    PORT
      LAYER M4 ;
        RECT 211.6500 0.0000 211.7500 0.5200 ;
    END
  END out[68]
  PIN out[67]
    DIRECTION OUTPUT ;
    USE SIGNAL ;
    PORT
      LAYER M4 ;
        RECT 209.6500 0.0000 209.7500 0.5200 ;
    END
  END out[67]
  PIN out[66]
    DIRECTION OUTPUT ;
    USE SIGNAL ;
    PORT
      LAYER M4 ;
        RECT 207.6500 0.0000 207.7500 0.5200 ;
    END
  END out[66]
  PIN out[65]
    DIRECTION OUTPUT ;
    USE SIGNAL ;
    PORT
      LAYER M4 ;
        RECT 205.6500 0.0000 205.7500 0.5200 ;
    END
  END out[65]
  PIN out[64]
    DIRECTION OUTPUT ;
    USE SIGNAL ;
    PORT
      LAYER M4 ;
        RECT 203.6500 0.0000 203.7500 0.5200 ;
    END
  END out[64]
  PIN out[63]
    DIRECTION OUTPUT ;
    USE SIGNAL ;
    PORT
      LAYER M4 ;
        RECT 201.6500 0.0000 201.7500 0.5200 ;
    END
  END out[63]
  PIN out[62]
    DIRECTION OUTPUT ;
    USE SIGNAL ;
    PORT
      LAYER M4 ;
        RECT 199.6500 0.0000 199.7500 0.5200 ;
    END
  END out[62]
  PIN out[61]
    DIRECTION OUTPUT ;
    USE SIGNAL ;
    PORT
      LAYER M4 ;
        RECT 197.6500 0.0000 197.7500 0.5200 ;
    END
  END out[61]
  PIN out[60]
    DIRECTION OUTPUT ;
    USE SIGNAL ;
    PORT
      LAYER M4 ;
        RECT 195.6500 0.0000 195.7500 0.5200 ;
    END
  END out[60]
  PIN out[59]
    DIRECTION OUTPUT ;
    USE SIGNAL ;
    PORT
      LAYER M4 ;
        RECT 193.6500 0.0000 193.7500 0.5200 ;
    END
  END out[59]
  PIN out[58]
    DIRECTION OUTPUT ;
    USE SIGNAL ;
    PORT
      LAYER M4 ;
        RECT 191.6500 0.0000 191.7500 0.5200 ;
    END
  END out[58]
  PIN out[57]
    DIRECTION OUTPUT ;
    USE SIGNAL ;
    PORT
      LAYER M4 ;
        RECT 189.6500 0.0000 189.7500 0.5200 ;
    END
  END out[57]
  PIN out[56]
    DIRECTION OUTPUT ;
    USE SIGNAL ;
    PORT
      LAYER M4 ;
        RECT 187.6500 0.0000 187.7500 0.5200 ;
    END
  END out[56]
  PIN out[55]
    DIRECTION OUTPUT ;
    USE SIGNAL ;
    PORT
      LAYER M4 ;
        RECT 185.6500 0.0000 185.7500 0.5200 ;
    END
  END out[55]
  PIN out[54]
    DIRECTION OUTPUT ;
    USE SIGNAL ;
    PORT
      LAYER M4 ;
        RECT 183.6500 0.0000 183.7500 0.5200 ;
    END
  END out[54]
  PIN out[53]
    DIRECTION OUTPUT ;
    USE SIGNAL ;
    PORT
      LAYER M4 ;
        RECT 181.6500 0.0000 181.7500 0.5200 ;
    END
  END out[53]
  PIN out[52]
    DIRECTION OUTPUT ;
    USE SIGNAL ;
    PORT
      LAYER M4 ;
        RECT 179.6500 0.0000 179.7500 0.5200 ;
    END
  END out[52]
  PIN out[51]
    DIRECTION OUTPUT ;
    USE SIGNAL ;
    PORT
      LAYER M4 ;
        RECT 177.6500 0.0000 177.7500 0.5200 ;
    END
  END out[51]
  PIN out[50]
    DIRECTION OUTPUT ;
    USE SIGNAL ;
    PORT
      LAYER M4 ;
        RECT 175.6500 0.0000 175.7500 0.5200 ;
    END
  END out[50]
  PIN out[49]
    DIRECTION OUTPUT ;
    USE SIGNAL ;
    PORT
      LAYER M4 ;
        RECT 173.6500 0.0000 173.7500 0.5200 ;
    END
  END out[49]
  PIN out[48]
    DIRECTION OUTPUT ;
    USE SIGNAL ;
    PORT
      LAYER M4 ;
        RECT 171.6500 0.0000 171.7500 0.5200 ;
    END
  END out[48]
  PIN out[47]
    DIRECTION OUTPUT ;
    USE SIGNAL ;
    PORT
      LAYER M4 ;
        RECT 169.6500 0.0000 169.7500 0.5200 ;
    END
  END out[47]
  PIN out[46]
    DIRECTION OUTPUT ;
    USE SIGNAL ;
    PORT
      LAYER M4 ;
        RECT 167.6500 0.0000 167.7500 0.5200 ;
    END
  END out[46]
  PIN out[45]
    DIRECTION OUTPUT ;
    USE SIGNAL ;
    PORT
      LAYER M4 ;
        RECT 165.6500 0.0000 165.7500 0.5200 ;
    END
  END out[45]
  PIN out[44]
    DIRECTION OUTPUT ;
    USE SIGNAL ;
    PORT
      LAYER M4 ;
        RECT 163.6500 0.0000 163.7500 0.5200 ;
    END
  END out[44]
  PIN out[43]
    DIRECTION OUTPUT ;
    USE SIGNAL ;
    PORT
      LAYER M4 ;
        RECT 161.6500 0.0000 161.7500 0.5200 ;
    END
  END out[43]
  PIN out[42]
    DIRECTION OUTPUT ;
    USE SIGNAL ;
    PORT
      LAYER M4 ;
        RECT 159.6500 0.0000 159.7500 0.5200 ;
    END
  END out[42]
  PIN out[41]
    DIRECTION OUTPUT ;
    USE SIGNAL ;
    PORT
      LAYER M4 ;
        RECT 157.6500 0.0000 157.7500 0.5200 ;
    END
  END out[41]
  PIN out[40]
    DIRECTION OUTPUT ;
    USE SIGNAL ;
    PORT
      LAYER M4 ;
        RECT 155.6500 0.0000 155.7500 0.5200 ;
    END
  END out[40]
  PIN out[39]
    DIRECTION OUTPUT ;
    USE SIGNAL ;
    PORT
      LAYER M4 ;
        RECT 153.6500 0.0000 153.7500 0.5200 ;
    END
  END out[39]
  PIN out[38]
    DIRECTION OUTPUT ;
    USE SIGNAL ;
    PORT
      LAYER M4 ;
        RECT 151.6500 0.0000 151.7500 0.5200 ;
    END
  END out[38]
  PIN out[37]
    DIRECTION OUTPUT ;
    USE SIGNAL ;
    PORT
      LAYER M4 ;
        RECT 149.6500 0.0000 149.7500 0.5200 ;
    END
  END out[37]
  PIN out[36]
    DIRECTION OUTPUT ;
    USE SIGNAL ;
    PORT
      LAYER M4 ;
        RECT 147.6500 0.0000 147.7500 0.5200 ;
    END
  END out[36]
  PIN out[35]
    DIRECTION OUTPUT ;
    USE SIGNAL ;
    PORT
      LAYER M4 ;
        RECT 145.6500 0.0000 145.7500 0.5200 ;
    END
  END out[35]
  PIN out[34]
    DIRECTION OUTPUT ;
    USE SIGNAL ;
    PORT
      LAYER M4 ;
        RECT 143.6500 0.0000 143.7500 0.5200 ;
    END
  END out[34]
  PIN out[33]
    DIRECTION OUTPUT ;
    USE SIGNAL ;
    PORT
      LAYER M4 ;
        RECT 141.6500 0.0000 141.7500 0.5200 ;
    END
  END out[33]
  PIN out[32]
    DIRECTION OUTPUT ;
    USE SIGNAL ;
    PORT
      LAYER M4 ;
        RECT 139.6500 0.0000 139.7500 0.5200 ;
    END
  END out[32]
  PIN out[31]
    DIRECTION OUTPUT ;
    USE SIGNAL ;
    PORT
      LAYER M4 ;
        RECT 137.6500 0.0000 137.7500 0.5200 ;
    END
  END out[31]
  PIN out[30]
    DIRECTION OUTPUT ;
    USE SIGNAL ;
    PORT
      LAYER M4 ;
        RECT 135.6500 0.0000 135.7500 0.5200 ;
    END
  END out[30]
  PIN out[29]
    DIRECTION OUTPUT ;
    USE SIGNAL ;
    PORT
      LAYER M4 ;
        RECT 133.6500 0.0000 133.7500 0.5200 ;
    END
  END out[29]
  PIN out[28]
    DIRECTION OUTPUT ;
    USE SIGNAL ;
    PORT
      LAYER M4 ;
        RECT 131.6500 0.0000 131.7500 0.5200 ;
    END
  END out[28]
  PIN out[27]
    DIRECTION OUTPUT ;
    USE SIGNAL ;
    PORT
      LAYER M4 ;
        RECT 129.6500 0.0000 129.7500 0.5200 ;
    END
  END out[27]
  PIN out[26]
    DIRECTION OUTPUT ;
    USE SIGNAL ;
    PORT
      LAYER M4 ;
        RECT 127.6500 0.0000 127.7500 0.5200 ;
    END
  END out[26]
  PIN out[25]
    DIRECTION OUTPUT ;
    USE SIGNAL ;
    PORT
      LAYER M4 ;
        RECT 125.6500 0.0000 125.7500 0.5200 ;
    END
  END out[25]
  PIN out[24]
    DIRECTION OUTPUT ;
    USE SIGNAL ;
    PORT
      LAYER M4 ;
        RECT 123.6500 0.0000 123.7500 0.5200 ;
    END
  END out[24]
  PIN out[23]
    DIRECTION OUTPUT ;
    USE SIGNAL ;
    PORT
      LAYER M4 ;
        RECT 121.6500 0.0000 121.7500 0.5200 ;
    END
  END out[23]
  PIN out[22]
    DIRECTION OUTPUT ;
    USE SIGNAL ;
    PORT
      LAYER M4 ;
        RECT 119.6500 0.0000 119.7500 0.5200 ;
    END
  END out[22]
  PIN out[21]
    DIRECTION OUTPUT ;
    USE SIGNAL ;
    PORT
      LAYER M4 ;
        RECT 117.6500 0.0000 117.7500 0.5200 ;
    END
  END out[21]
  PIN out[20]
    DIRECTION OUTPUT ;
    USE SIGNAL ;
    PORT
      LAYER M4 ;
        RECT 115.6500 0.0000 115.7500 0.5200 ;
    END
  END out[20]
  PIN out[19]
    DIRECTION OUTPUT ;
    USE SIGNAL ;
    PORT
      LAYER M4 ;
        RECT 113.6500 0.0000 113.7500 0.5200 ;
    END
  END out[19]
  PIN out[18]
    DIRECTION OUTPUT ;
    USE SIGNAL ;
    PORT
      LAYER M4 ;
        RECT 111.6500 0.0000 111.7500 0.5200 ;
    END
  END out[18]
  PIN out[17]
    DIRECTION OUTPUT ;
    USE SIGNAL ;
    PORT
      LAYER M4 ;
        RECT 109.6500 0.0000 109.7500 0.5200 ;
    END
  END out[17]
  PIN out[16]
    DIRECTION OUTPUT ;
    USE SIGNAL ;
    PORT
      LAYER M4 ;
        RECT 107.6500 0.0000 107.7500 0.5200 ;
    END
  END out[16]
  PIN out[15]
    DIRECTION OUTPUT ;
    USE SIGNAL ;
    PORT
      LAYER M4 ;
        RECT 105.6500 0.0000 105.7500 0.5200 ;
    END
  END out[15]
  PIN out[14]
    DIRECTION OUTPUT ;
    USE SIGNAL ;
    PORT
      LAYER M4 ;
        RECT 103.6500 0.0000 103.7500 0.5200 ;
    END
  END out[14]
  PIN out[13]
    DIRECTION OUTPUT ;
    USE SIGNAL ;
    PORT
      LAYER M4 ;
        RECT 101.6500 0.0000 101.7500 0.5200 ;
    END
  END out[13]
  PIN out[12]
    DIRECTION OUTPUT ;
    USE SIGNAL ;
    PORT
      LAYER M4 ;
        RECT 99.6500 0.0000 99.7500 0.5200 ;
    END
  END out[12]
  PIN out[11]
    DIRECTION OUTPUT ;
    USE SIGNAL ;
    PORT
      LAYER M4 ;
        RECT 97.6500 0.0000 97.7500 0.5200 ;
    END
  END out[11]
  PIN out[10]
    DIRECTION OUTPUT ;
    USE SIGNAL ;
    PORT
      LAYER M4 ;
        RECT 95.6500 0.0000 95.7500 0.5200 ;
    END
  END out[10]
  PIN out[9]
    DIRECTION OUTPUT ;
    USE SIGNAL ;
    PORT
      LAYER M4 ;
        RECT 93.6500 0.0000 93.7500 0.5200 ;
    END
  END out[9]
  PIN out[8]
    DIRECTION OUTPUT ;
    USE SIGNAL ;
    PORT
      LAYER M4 ;
        RECT 91.6500 0.0000 91.7500 0.5200 ;
    END
  END out[8]
  PIN out[7]
    DIRECTION OUTPUT ;
    USE SIGNAL ;
    PORT
      LAYER M4 ;
        RECT 89.6500 0.0000 89.7500 0.5200 ;
    END
  END out[7]
  PIN out[6]
    DIRECTION OUTPUT ;
    USE SIGNAL ;
    PORT
      LAYER M4 ;
        RECT 87.6500 0.0000 87.7500 0.5200 ;
    END
  END out[6]
  PIN out[5]
    DIRECTION OUTPUT ;
    USE SIGNAL ;
    PORT
      LAYER M4 ;
        RECT 85.6500 0.0000 85.7500 0.5200 ;
    END
  END out[5]
  PIN out[4]
    DIRECTION OUTPUT ;
    USE SIGNAL ;
    PORT
      LAYER M4 ;
        RECT 83.6500 0.0000 83.7500 0.5200 ;
    END
  END out[4]
  PIN out[3]
    DIRECTION OUTPUT ;
    USE SIGNAL ;
    PORT
      LAYER M4 ;
        RECT 81.6500 0.0000 81.7500 0.5200 ;
    END
  END out[3]
  PIN out[2]
    DIRECTION OUTPUT ;
    USE SIGNAL ;
    PORT
      LAYER M4 ;
        RECT 79.6500 0.0000 79.7500 0.5200 ;
    END
  END out[2]
  PIN out[1]
    DIRECTION OUTPUT ;
    USE SIGNAL ;
    PORT
      LAYER M4 ;
        RECT 77.6500 0.0000 77.7500 0.5200 ;
    END
  END out[1]
  PIN out[0]
    DIRECTION OUTPUT ;
    USE SIGNAL ;
    PORT
      LAYER M4 ;
        RECT 75.6500 0.0000 75.7500 0.5200 ;
    END
  END out[0]
  OBS
    LAYER M1 ;
      RECT 0.0000 0.0000 453.0000 452.2000 ;
    LAYER M2 ;
      RECT 0.0000 0.0000 453.0000 452.2000 ;
    LAYER M3 ;
      RECT 0.0000 394.1500 453.0000 452.2000 ;
      RECT 0.6200 393.8500 453.0000 394.1500 ;
      RECT 0.0000 390.1500 453.0000 393.8500 ;
      RECT 0.6200 389.8500 453.0000 390.1500 ;
      RECT 0.0000 386.1500 453.0000 389.8500 ;
      RECT 0.6200 385.8500 453.0000 386.1500 ;
      RECT 0.0000 382.1500 453.0000 385.8500 ;
      RECT 0.6200 381.8500 453.0000 382.1500 ;
      RECT 0.0000 378.1500 453.0000 381.8500 ;
      RECT 0.6200 377.8500 453.0000 378.1500 ;
      RECT 0.0000 374.1500 453.0000 377.8500 ;
      RECT 0.6200 373.8500 453.0000 374.1500 ;
      RECT 0.0000 370.1500 453.0000 373.8500 ;
      RECT 0.6200 369.8500 453.0000 370.1500 ;
      RECT 0.0000 366.1500 453.0000 369.8500 ;
      RECT 0.6200 365.8500 453.0000 366.1500 ;
      RECT 0.0000 362.1500 453.0000 365.8500 ;
      RECT 0.6200 361.8500 453.0000 362.1500 ;
      RECT 0.0000 358.1500 453.0000 361.8500 ;
      RECT 0.6200 357.8500 453.0000 358.1500 ;
      RECT 0.0000 354.1500 453.0000 357.8500 ;
      RECT 0.6200 353.8500 453.0000 354.1500 ;
      RECT 0.0000 350.1500 453.0000 353.8500 ;
      RECT 0.6200 349.8500 453.0000 350.1500 ;
      RECT 0.0000 346.1500 453.0000 349.8500 ;
      RECT 0.6200 345.8500 453.0000 346.1500 ;
      RECT 0.0000 342.1500 453.0000 345.8500 ;
      RECT 0.6200 341.8500 453.0000 342.1500 ;
      RECT 0.0000 338.1500 453.0000 341.8500 ;
      RECT 0.6200 337.8500 453.0000 338.1500 ;
      RECT 0.0000 334.1500 453.0000 337.8500 ;
      RECT 0.6200 333.8500 453.0000 334.1500 ;
      RECT 0.0000 330.1500 453.0000 333.8500 ;
      RECT 0.6200 329.8500 453.0000 330.1500 ;
      RECT 0.0000 326.1500 453.0000 329.8500 ;
      RECT 0.6200 325.8500 453.0000 326.1500 ;
      RECT 0.0000 322.1500 453.0000 325.8500 ;
      RECT 0.6200 321.8500 453.0000 322.1500 ;
      RECT 0.0000 318.1500 453.0000 321.8500 ;
      RECT 0.6200 317.8500 453.0000 318.1500 ;
      RECT 0.0000 314.1500 453.0000 317.8500 ;
      RECT 0.6200 313.8500 453.0000 314.1500 ;
      RECT 0.0000 310.1500 453.0000 313.8500 ;
      RECT 0.6200 309.8500 453.0000 310.1500 ;
      RECT 0.0000 306.1500 453.0000 309.8500 ;
      RECT 0.6200 305.8500 453.0000 306.1500 ;
      RECT 0.0000 302.1500 453.0000 305.8500 ;
      RECT 0.6200 301.8500 453.0000 302.1500 ;
      RECT 0.0000 298.1500 453.0000 301.8500 ;
      RECT 0.6200 297.8500 453.0000 298.1500 ;
      RECT 0.0000 294.1500 453.0000 297.8500 ;
      RECT 0.6200 293.8500 453.0000 294.1500 ;
      RECT 0.0000 290.1500 453.0000 293.8500 ;
      RECT 0.6200 289.8500 453.0000 290.1500 ;
      RECT 0.0000 286.1500 453.0000 289.8500 ;
      RECT 0.6200 285.8500 453.0000 286.1500 ;
      RECT 0.0000 282.1500 453.0000 285.8500 ;
      RECT 0.6200 281.8500 453.0000 282.1500 ;
      RECT 0.0000 278.1500 453.0000 281.8500 ;
      RECT 0.6200 277.8500 453.0000 278.1500 ;
      RECT 0.0000 274.1500 453.0000 277.8500 ;
      RECT 0.6200 273.8500 453.0000 274.1500 ;
      RECT 0.0000 270.1500 453.0000 273.8500 ;
      RECT 0.6200 269.8500 453.0000 270.1500 ;
      RECT 0.0000 266.1500 453.0000 269.8500 ;
      RECT 0.6200 265.8500 453.0000 266.1500 ;
      RECT 0.0000 262.1500 453.0000 265.8500 ;
      RECT 0.6200 261.8500 453.0000 262.1500 ;
      RECT 0.0000 258.1500 453.0000 261.8500 ;
      RECT 0.6200 257.8500 453.0000 258.1500 ;
      RECT 0.0000 254.1500 453.0000 257.8500 ;
      RECT 0.6200 253.8500 453.0000 254.1500 ;
      RECT 0.0000 250.1500 453.0000 253.8500 ;
      RECT 0.6200 249.8500 453.0000 250.1500 ;
      RECT 0.0000 246.1500 453.0000 249.8500 ;
      RECT 0.6200 245.8500 453.0000 246.1500 ;
      RECT 0.0000 242.1500 453.0000 245.8500 ;
      RECT 0.6200 241.8500 453.0000 242.1500 ;
      RECT 0.0000 238.1500 453.0000 241.8500 ;
      RECT 0.6200 237.8500 453.0000 238.1500 ;
      RECT 0.0000 234.1500 453.0000 237.8500 ;
      RECT 0.6200 233.8500 453.0000 234.1500 ;
      RECT 0.0000 230.1500 453.0000 233.8500 ;
      RECT 0.6200 229.8500 453.0000 230.1500 ;
      RECT 0.0000 226.1500 453.0000 229.8500 ;
      RECT 0.6200 225.8500 453.0000 226.1500 ;
      RECT 0.0000 222.1500 453.0000 225.8500 ;
      RECT 0.6200 221.8500 453.0000 222.1500 ;
      RECT 0.0000 218.1500 453.0000 221.8500 ;
      RECT 0.6200 217.8500 453.0000 218.1500 ;
      RECT 0.0000 214.1500 453.0000 217.8500 ;
      RECT 0.6200 213.8500 453.0000 214.1500 ;
      RECT 0.0000 210.1500 453.0000 213.8500 ;
      RECT 0.6200 209.8500 453.0000 210.1500 ;
      RECT 0.0000 206.1500 453.0000 209.8500 ;
      RECT 0.6200 205.8500 453.0000 206.1500 ;
      RECT 0.0000 202.1500 453.0000 205.8500 ;
      RECT 0.6200 201.8500 453.0000 202.1500 ;
      RECT 0.0000 198.1500 453.0000 201.8500 ;
      RECT 0.6200 197.8500 453.0000 198.1500 ;
      RECT 0.0000 194.1500 453.0000 197.8500 ;
      RECT 0.6200 193.8500 453.0000 194.1500 ;
      RECT 0.0000 190.1500 453.0000 193.8500 ;
      RECT 0.6200 189.8500 453.0000 190.1500 ;
      RECT 0.0000 186.1500 453.0000 189.8500 ;
      RECT 0.6200 185.8500 453.0000 186.1500 ;
      RECT 0.0000 182.1500 453.0000 185.8500 ;
      RECT 0.6200 181.8500 453.0000 182.1500 ;
      RECT 0.0000 178.1500 453.0000 181.8500 ;
      RECT 0.6200 177.8500 453.0000 178.1500 ;
      RECT 0.0000 174.1500 453.0000 177.8500 ;
      RECT 0.6200 173.8500 453.0000 174.1500 ;
      RECT 0.0000 170.1500 453.0000 173.8500 ;
      RECT 0.6200 169.8500 453.0000 170.1500 ;
      RECT 0.0000 166.1500 453.0000 169.8500 ;
      RECT 0.6200 165.8500 453.0000 166.1500 ;
      RECT 0.0000 162.1500 453.0000 165.8500 ;
      RECT 0.6200 161.8500 453.0000 162.1500 ;
      RECT 0.0000 158.1500 453.0000 161.8500 ;
      RECT 0.6200 157.8500 453.0000 158.1500 ;
      RECT 0.0000 154.1500 453.0000 157.8500 ;
      RECT 0.6200 153.8500 453.0000 154.1500 ;
      RECT 0.0000 150.1500 453.0000 153.8500 ;
      RECT 0.6200 149.8500 453.0000 150.1500 ;
      RECT 0.0000 146.1500 453.0000 149.8500 ;
      RECT 0.6200 145.8500 453.0000 146.1500 ;
      RECT 0.0000 142.1500 453.0000 145.8500 ;
      RECT 0.6200 141.8500 453.0000 142.1500 ;
      RECT 0.0000 138.1500 453.0000 141.8500 ;
      RECT 0.6200 137.8500 453.0000 138.1500 ;
      RECT 0.0000 134.1500 453.0000 137.8500 ;
      RECT 0.6200 133.8500 453.0000 134.1500 ;
      RECT 0.0000 130.1500 453.0000 133.8500 ;
      RECT 0.6200 129.8500 453.0000 130.1500 ;
      RECT 0.0000 126.1500 453.0000 129.8500 ;
      RECT 0.6200 125.8500 453.0000 126.1500 ;
      RECT 0.0000 122.1500 453.0000 125.8500 ;
      RECT 0.6200 121.8500 453.0000 122.1500 ;
      RECT 0.0000 118.1500 453.0000 121.8500 ;
      RECT 0.6200 117.8500 453.0000 118.1500 ;
      RECT 0.0000 114.1500 453.0000 117.8500 ;
      RECT 0.6200 113.8500 453.0000 114.1500 ;
      RECT 0.0000 110.1500 453.0000 113.8500 ;
      RECT 0.6200 109.8500 453.0000 110.1500 ;
      RECT 0.0000 106.1500 453.0000 109.8500 ;
      RECT 0.6200 105.8500 453.0000 106.1500 ;
      RECT 0.0000 102.1500 453.0000 105.8500 ;
      RECT 0.6200 101.8500 453.0000 102.1500 ;
      RECT 0.0000 98.1500 453.0000 101.8500 ;
      RECT 0.6200 97.8500 453.0000 98.1500 ;
      RECT 0.0000 94.1500 453.0000 97.8500 ;
      RECT 0.6200 93.8500 453.0000 94.1500 ;
      RECT 0.0000 90.1500 453.0000 93.8500 ;
      RECT 0.6200 89.8500 453.0000 90.1500 ;
      RECT 0.0000 86.1500 453.0000 89.8500 ;
      RECT 0.6200 85.8500 453.0000 86.1500 ;
      RECT 0.0000 82.1500 453.0000 85.8500 ;
      RECT 0.6200 81.8500 453.0000 82.1500 ;
      RECT 0.0000 78.1500 453.0000 81.8500 ;
      RECT 0.6200 77.8500 453.0000 78.1500 ;
      RECT 0.0000 74.1500 453.0000 77.8500 ;
      RECT 0.6200 73.8500 453.0000 74.1500 ;
      RECT 0.0000 70.1500 453.0000 73.8500 ;
      RECT 0.6200 69.8500 453.0000 70.1500 ;
      RECT 0.0000 66.1500 453.0000 69.8500 ;
      RECT 0.6200 65.8500 453.0000 66.1500 ;
      RECT 0.0000 62.1500 453.0000 65.8500 ;
      RECT 0.6200 61.8500 453.0000 62.1500 ;
      RECT 0.0000 58.1500 453.0000 61.8500 ;
      RECT 0.6200 57.8500 453.0000 58.1500 ;
      RECT 0.0000 0.0000 453.0000 57.8500 ;
    LAYER M4 ;
      RECT 0.0000 0.6200 453.0000 452.2000 ;
      RECT 377.8500 0.0000 453.0000 0.6200 ;
      RECT 375.8500 0.0000 377.5500 0.6200 ;
      RECT 373.8500 0.0000 375.5500 0.6200 ;
      RECT 371.8500 0.0000 373.5500 0.6200 ;
      RECT 369.8500 0.0000 371.5500 0.6200 ;
      RECT 367.8500 0.0000 369.5500 0.6200 ;
      RECT 365.8500 0.0000 367.5500 0.6200 ;
      RECT 363.8500 0.0000 365.5500 0.6200 ;
      RECT 361.8500 0.0000 363.5500 0.6200 ;
      RECT 359.8500 0.0000 361.5500 0.6200 ;
      RECT 357.8500 0.0000 359.5500 0.6200 ;
      RECT 355.8500 0.0000 357.5500 0.6200 ;
      RECT 353.8500 0.0000 355.5500 0.6200 ;
      RECT 351.8500 0.0000 353.5500 0.6200 ;
      RECT 349.8500 0.0000 351.5500 0.6200 ;
      RECT 347.8500 0.0000 349.5500 0.6200 ;
      RECT 345.8500 0.0000 347.5500 0.6200 ;
      RECT 343.8500 0.0000 345.5500 0.6200 ;
      RECT 341.8500 0.0000 343.5500 0.6200 ;
      RECT 339.8500 0.0000 341.5500 0.6200 ;
      RECT 337.8500 0.0000 339.5500 0.6200 ;
      RECT 335.8500 0.0000 337.5500 0.6200 ;
      RECT 333.8500 0.0000 335.5500 0.6200 ;
      RECT 331.8500 0.0000 333.5500 0.6200 ;
      RECT 329.8500 0.0000 331.5500 0.6200 ;
      RECT 327.8500 0.0000 329.5500 0.6200 ;
      RECT 325.8500 0.0000 327.5500 0.6200 ;
      RECT 323.8500 0.0000 325.5500 0.6200 ;
      RECT 321.8500 0.0000 323.5500 0.6200 ;
      RECT 319.8500 0.0000 321.5500 0.6200 ;
      RECT 317.8500 0.0000 319.5500 0.6200 ;
      RECT 315.8500 0.0000 317.5500 0.6200 ;
      RECT 313.8500 0.0000 315.5500 0.6200 ;
      RECT 311.8500 0.0000 313.5500 0.6200 ;
      RECT 309.8500 0.0000 311.5500 0.6200 ;
      RECT 307.8500 0.0000 309.5500 0.6200 ;
      RECT 305.8500 0.0000 307.5500 0.6200 ;
      RECT 303.8500 0.0000 305.5500 0.6200 ;
      RECT 301.8500 0.0000 303.5500 0.6200 ;
      RECT 299.8500 0.0000 301.5500 0.6200 ;
      RECT 297.8500 0.0000 299.5500 0.6200 ;
      RECT 295.8500 0.0000 297.5500 0.6200 ;
      RECT 293.8500 0.0000 295.5500 0.6200 ;
      RECT 291.8500 0.0000 293.5500 0.6200 ;
      RECT 289.8500 0.0000 291.5500 0.6200 ;
      RECT 287.8500 0.0000 289.5500 0.6200 ;
      RECT 285.8500 0.0000 287.5500 0.6200 ;
      RECT 283.8500 0.0000 285.5500 0.6200 ;
      RECT 281.8500 0.0000 283.5500 0.6200 ;
      RECT 279.8500 0.0000 281.5500 0.6200 ;
      RECT 277.8500 0.0000 279.5500 0.6200 ;
      RECT 275.8500 0.0000 277.5500 0.6200 ;
      RECT 273.8500 0.0000 275.5500 0.6200 ;
      RECT 271.8500 0.0000 273.5500 0.6200 ;
      RECT 269.8500 0.0000 271.5500 0.6200 ;
      RECT 267.8500 0.0000 269.5500 0.6200 ;
      RECT 265.8500 0.0000 267.5500 0.6200 ;
      RECT 263.8500 0.0000 265.5500 0.6200 ;
      RECT 261.8500 0.0000 263.5500 0.6200 ;
      RECT 259.8500 0.0000 261.5500 0.6200 ;
      RECT 257.8500 0.0000 259.5500 0.6200 ;
      RECT 255.8500 0.0000 257.5500 0.6200 ;
      RECT 253.8500 0.0000 255.5500 0.6200 ;
      RECT 251.8500 0.0000 253.5500 0.6200 ;
      RECT 249.8500 0.0000 251.5500 0.6200 ;
      RECT 247.8500 0.0000 249.5500 0.6200 ;
      RECT 245.8500 0.0000 247.5500 0.6200 ;
      RECT 243.8500 0.0000 245.5500 0.6200 ;
      RECT 241.8500 0.0000 243.5500 0.6200 ;
      RECT 239.8500 0.0000 241.5500 0.6200 ;
      RECT 237.8500 0.0000 239.5500 0.6200 ;
      RECT 235.8500 0.0000 237.5500 0.6200 ;
      RECT 233.8500 0.0000 235.5500 0.6200 ;
      RECT 231.8500 0.0000 233.5500 0.6200 ;
      RECT 229.8500 0.0000 231.5500 0.6200 ;
      RECT 227.8500 0.0000 229.5500 0.6200 ;
      RECT 225.8500 0.0000 227.5500 0.6200 ;
      RECT 223.8500 0.0000 225.5500 0.6200 ;
      RECT 221.8500 0.0000 223.5500 0.6200 ;
      RECT 219.8500 0.0000 221.5500 0.6200 ;
      RECT 217.8500 0.0000 219.5500 0.6200 ;
      RECT 215.8500 0.0000 217.5500 0.6200 ;
      RECT 213.8500 0.0000 215.5500 0.6200 ;
      RECT 211.8500 0.0000 213.5500 0.6200 ;
      RECT 209.8500 0.0000 211.5500 0.6200 ;
      RECT 207.8500 0.0000 209.5500 0.6200 ;
      RECT 205.8500 0.0000 207.5500 0.6200 ;
      RECT 203.8500 0.0000 205.5500 0.6200 ;
      RECT 201.8500 0.0000 203.5500 0.6200 ;
      RECT 199.8500 0.0000 201.5500 0.6200 ;
      RECT 197.8500 0.0000 199.5500 0.6200 ;
      RECT 195.8500 0.0000 197.5500 0.6200 ;
      RECT 193.8500 0.0000 195.5500 0.6200 ;
      RECT 191.8500 0.0000 193.5500 0.6200 ;
      RECT 189.8500 0.0000 191.5500 0.6200 ;
      RECT 187.8500 0.0000 189.5500 0.6200 ;
      RECT 185.8500 0.0000 187.5500 0.6200 ;
      RECT 183.8500 0.0000 185.5500 0.6200 ;
      RECT 181.8500 0.0000 183.5500 0.6200 ;
      RECT 179.8500 0.0000 181.5500 0.6200 ;
      RECT 177.8500 0.0000 179.5500 0.6200 ;
      RECT 175.8500 0.0000 177.5500 0.6200 ;
      RECT 173.8500 0.0000 175.5500 0.6200 ;
      RECT 171.8500 0.0000 173.5500 0.6200 ;
      RECT 169.8500 0.0000 171.5500 0.6200 ;
      RECT 167.8500 0.0000 169.5500 0.6200 ;
      RECT 165.8500 0.0000 167.5500 0.6200 ;
      RECT 163.8500 0.0000 165.5500 0.6200 ;
      RECT 161.8500 0.0000 163.5500 0.6200 ;
      RECT 159.8500 0.0000 161.5500 0.6200 ;
      RECT 157.8500 0.0000 159.5500 0.6200 ;
      RECT 155.8500 0.0000 157.5500 0.6200 ;
      RECT 153.8500 0.0000 155.5500 0.6200 ;
      RECT 151.8500 0.0000 153.5500 0.6200 ;
      RECT 149.8500 0.0000 151.5500 0.6200 ;
      RECT 147.8500 0.0000 149.5500 0.6200 ;
      RECT 145.8500 0.0000 147.5500 0.6200 ;
      RECT 143.8500 0.0000 145.5500 0.6200 ;
      RECT 141.8500 0.0000 143.5500 0.6200 ;
      RECT 139.8500 0.0000 141.5500 0.6200 ;
      RECT 137.8500 0.0000 139.5500 0.6200 ;
      RECT 135.8500 0.0000 137.5500 0.6200 ;
      RECT 133.8500 0.0000 135.5500 0.6200 ;
      RECT 131.8500 0.0000 133.5500 0.6200 ;
      RECT 129.8500 0.0000 131.5500 0.6200 ;
      RECT 127.8500 0.0000 129.5500 0.6200 ;
      RECT 125.8500 0.0000 127.5500 0.6200 ;
      RECT 123.8500 0.0000 125.5500 0.6200 ;
      RECT 121.8500 0.0000 123.5500 0.6200 ;
      RECT 119.8500 0.0000 121.5500 0.6200 ;
      RECT 117.8500 0.0000 119.5500 0.6200 ;
      RECT 115.8500 0.0000 117.5500 0.6200 ;
      RECT 113.8500 0.0000 115.5500 0.6200 ;
      RECT 111.8500 0.0000 113.5500 0.6200 ;
      RECT 109.8500 0.0000 111.5500 0.6200 ;
      RECT 107.8500 0.0000 109.5500 0.6200 ;
      RECT 105.8500 0.0000 107.5500 0.6200 ;
      RECT 103.8500 0.0000 105.5500 0.6200 ;
      RECT 101.8500 0.0000 103.5500 0.6200 ;
      RECT 99.8500 0.0000 101.5500 0.6200 ;
      RECT 97.8500 0.0000 99.5500 0.6200 ;
      RECT 95.8500 0.0000 97.5500 0.6200 ;
      RECT 93.8500 0.0000 95.5500 0.6200 ;
      RECT 91.8500 0.0000 93.5500 0.6200 ;
      RECT 89.8500 0.0000 91.5500 0.6200 ;
      RECT 87.8500 0.0000 89.5500 0.6200 ;
      RECT 85.8500 0.0000 87.5500 0.6200 ;
      RECT 83.8500 0.0000 85.5500 0.6200 ;
      RECT 81.8500 0.0000 83.5500 0.6200 ;
      RECT 79.8500 0.0000 81.5500 0.6200 ;
      RECT 77.8500 0.0000 79.5500 0.6200 ;
      RECT 75.8500 0.0000 77.5500 0.6200 ;
      RECT 0.0000 0.0000 75.5500 0.6200 ;
    LAYER M5 ;
      RECT 0.0000 0.0000 453.0000 452.2000 ;
    LAYER M6 ;
      RECT 0.0000 0.0000 453.0000 452.2000 ;
    LAYER M7 ;
      RECT 0.0000 0.0000 453.0000 452.2000 ;
    LAYER M8 ;
      RECT 0.0000 0.0000 453.0000 452.2000 ;
  END
END core

END LIBRARY
